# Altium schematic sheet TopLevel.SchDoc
size A4; SheetNumber: 1; SheetTotal: 1

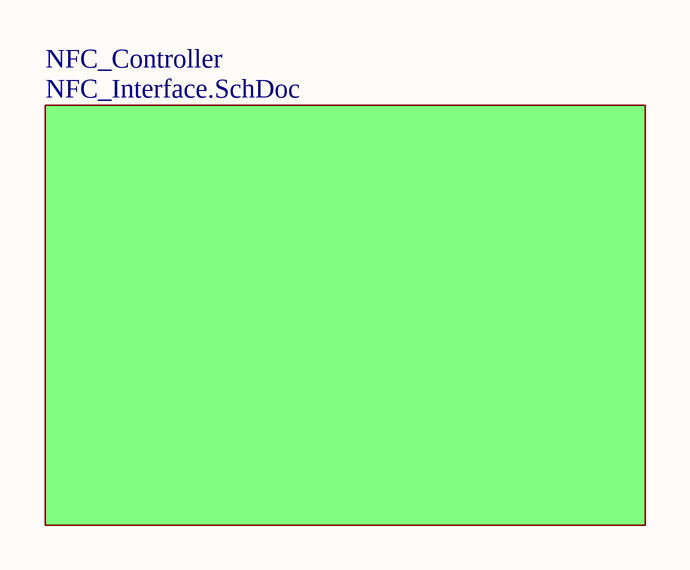
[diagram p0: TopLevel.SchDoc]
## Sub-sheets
NFC_Controller = NFC_Interface.SchDoc: no entries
